VERSION 5.7 ;
  NOWIREEXTENSIONATPIN ON ;
  DIVIDERCHAR "/" ;
  BUSBITCHARS "[]" ;
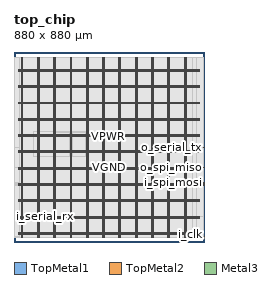
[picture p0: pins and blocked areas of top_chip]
MACRO top_chip
  CLASS BLOCK ;
  FOREIGN top_chip ;
  ORIGIN 0.000 0.000 ;
  SIZE 880.000 BY 880.000 ;
  PIN VGND
    DIRECTION INOUT ;
    USE GROUND ;
    PORT
      LAYER TopMetal1 ;
        RECT 38.860 22.050 41.060 854.910 ;
    END
    PORT
      LAYER TopMetal1 ;
        RECT 114.460 22.050 116.660 854.910 ;
    END
    PORT
      LAYER TopMetal1 ;
        RECT 190.060 22.050 192.260 854.910 ;
    END
    PORT
      LAYER TopMetal1 ;
        RECT 265.660 22.050 267.860 854.910 ;
    END
    PORT
      LAYER TopMetal1 ;
        RECT 341.260 22.050 343.460 854.910 ;
    END
    PORT
      LAYER TopMetal1 ;
        RECT 416.860 22.050 419.060 854.910 ;
    END
    PORT
      LAYER TopMetal1 ;
        RECT 492.460 22.050 494.660 854.910 ;
    END
    PORT
      LAYER TopMetal1 ;
        RECT 568.060 22.050 570.260 854.910 ;
    END
    PORT
      LAYER TopMetal1 ;
        RECT 643.660 22.050 645.860 854.910 ;
    END
    PORT
      LAYER TopMetal1 ;
        RECT 719.260 22.050 721.460 854.910 ;
    END
    PORT
      LAYER TopMetal1 ;
        RECT 794.860 22.050 797.060 854.910 ;
    END
    PORT
      LAYER TopMetal2 ;
        RECT 19.940 41.380 859.900 43.580 ;
    END
    PORT
      LAYER TopMetal2 ;
        RECT 19.940 116.980 859.900 119.180 ;
    END
    PORT
      LAYER TopMetal2 ;
        RECT 19.940 192.580 859.900 194.780 ;
    END
    PORT
      LAYER TopMetal2 ;
        RECT 19.940 268.180 859.900 270.380 ;
    END
    PORT
      LAYER TopMetal2 ;
        RECT 19.940 343.780 859.900 345.980 ;
    END
    PORT
      LAYER TopMetal2 ;
        RECT 19.940 419.380 859.900 421.580 ;
    END
    PORT
      LAYER TopMetal2 ;
        RECT 19.940 494.980 859.900 497.180 ;
    END
    PORT
      LAYER TopMetal2 ;
        RECT 19.940 570.580 859.900 572.780 ;
    END
    PORT
      LAYER TopMetal2 ;
        RECT 19.940 646.180 859.900 648.380 ;
    END
    PORT
      LAYER TopMetal2 ;
        RECT 19.940 721.780 859.900 723.980 ;
    END
    PORT
      LAYER TopMetal2 ;
        RECT 19.940 797.380 859.900 799.580 ;
    END
  END VGND
  PIN VPWR
    DIRECTION INOUT ;
    USE POWER ;
    PORT
      LAYER TopMetal1 ;
        RECT 32.660 22.460 34.860 854.500 ;
    END
    PORT
      LAYER TopMetal1 ;
        RECT 108.260 22.460 110.460 854.500 ;
    END
    PORT
      LAYER TopMetal1 ;
        RECT 183.860 22.460 186.060 854.500 ;
    END
    PORT
      LAYER TopMetal1 ;
        RECT 259.460 22.460 261.660 854.500 ;
    END
    PORT
      LAYER TopMetal1 ;
        RECT 335.060 22.460 337.260 854.500 ;
    END
    PORT
      LAYER TopMetal1 ;
        RECT 410.660 22.460 412.860 854.500 ;
    END
    PORT
      LAYER TopMetal1 ;
        RECT 486.260 22.460 488.460 854.500 ;
    END
    PORT
      LAYER TopMetal1 ;
        RECT 561.860 22.460 564.060 854.500 ;
    END
    PORT
      LAYER TopMetal1 ;
        RECT 637.460 22.460 639.660 854.500 ;
    END
    PORT
      LAYER TopMetal1 ;
        RECT 713.060 22.460 715.260 854.500 ;
    END
    PORT
      LAYER TopMetal1 ;
        RECT 788.660 22.460 790.860 854.500 ;
    END
    PORT
      LAYER TopMetal2 ;
        RECT 19.940 35.180 859.900 37.380 ;
    END
    PORT
      LAYER TopMetal2 ;
        RECT 19.940 110.780 859.900 112.980 ;
    END
    PORT
      LAYER TopMetal2 ;
        RECT 19.940 186.380 859.900 188.580 ;
    END
    PORT
      LAYER TopMetal2 ;
        RECT 19.940 261.980 859.900 264.180 ;
    END
    PORT
      LAYER TopMetal2 ;
        RECT 19.940 337.580 859.900 339.780 ;
    END
    PORT
      LAYER TopMetal2 ;
        RECT 19.940 413.180 859.900 415.380 ;
    END
    PORT
      LAYER TopMetal2 ;
        RECT 19.940 488.780 859.900 490.980 ;
    END
    PORT
      LAYER TopMetal2 ;
        RECT 19.940 564.380 859.900 566.580 ;
    END
    PORT
      LAYER TopMetal2 ;
        RECT 19.940 639.980 859.900 642.180 ;
    END
    PORT
      LAYER TopMetal2 ;
        RECT 19.940 715.580 859.900 717.780 ;
    END
    PORT
      LAYER TopMetal2 ;
        RECT 19.940 791.180 859.900 793.380 ;
    END
  END VPWR
  PIN i_clk
    DIRECTION INPUT ;
    USE SIGNAL ;
    ANTENNAGATEAREA 1.333800 ;
    ANTENNADIFFAREA 2.015400 ;
    PORT
      LAYER Metal3 ;
        RECT 879.600 27.100 880.000 27.500 ;
    END
  END i_clk
  PIN i_rst_n
    DIRECTION INPUT ;
    USE SIGNAL ;
    ANTENNAGATEAREA 0.180700 ;
    PORT
      LAYER Metal3 ;
        RECT 879.600 259.780 880.000 260.180 ;
    END
  END i_rst_n
  PIN i_serial_rx
    DIRECTION INPUT ;
    USE SIGNAL ;
    ANTENNAGATEAREA 0.180700 ;
    PORT
      LAYER Metal3 ;
        RECT 0.000 116.980 0.400 117.380 ;
    END
  END i_serial_rx
  PIN i_spi_mosi
    DIRECTION INPUT ;
    USE SIGNAL ;
    ANTENNAGATEAREA 0.180700 ;
    PORT
      LAYER Metal3 ;
        RECT 879.600 275.740 880.000 276.140 ;
    END
  END i_spi_mosi
  PIN i_spi_sclk
    DIRECTION INPUT ;
    USE SIGNAL ;
    ANTENNAGATEAREA 0.180700 ;
    PORT
      LAYER Metal3 ;
        RECT 879.600 267.340 880.000 267.740 ;
    END
  END i_spi_sclk
  PIN i_spi_ss_n
    DIRECTION INPUT ;
    USE SIGNAL ;
    ANTENNAGATEAREA 0.180700 ;
    PORT
      LAYER Metal3 ;
        RECT 879.600 269.020 880.000 269.420 ;
    END
  END i_spi_ss_n
  PIN o_serial_tx
    DIRECTION OUTPUT ;
    USE SIGNAL ;
    ANTENNADIFFAREA 0.708600 ;
    PORT
      LAYER Metal3 ;
        RECT 879.600 438.700 880.000 439.100 ;
    END
  END o_serial_tx
  PIN o_spi_miso
    DIRECTION OUTPUT ;
    USE SIGNAL ;
    ANTENNADIFFAREA 2.827200 ;
    PORT
      LAYER Metal3 ;
        RECT 879.600 345.460 880.000 345.860 ;
    END
  END o_spi_miso
  OBS
      LAYER GatPoly ;
        RECT 20.160 22.530 859.680 854.430 ;
      LAYER Metal1 ;
        RECT 20.160 22.460 859.680 854.500 ;
      LAYER Metal2 ;
        RECT 20.535 22.535 879.945 854.425 ;
      LAYER Metal3 ;
        RECT 0.400 439.310 879.985 854.380 ;
        RECT 0.400 438.490 879.390 439.310 ;
        RECT 0.400 346.070 879.985 438.490 ;
        RECT 0.400 345.250 879.390 346.070 ;
        RECT 0.400 276.350 879.985 345.250 ;
        RECT 0.400 275.530 879.390 276.350 ;
        RECT 0.400 269.630 879.985 275.530 ;
        RECT 0.400 268.810 879.390 269.630 ;
        RECT 0.400 267.950 879.985 268.810 ;
        RECT 0.400 267.130 879.390 267.950 ;
        RECT 0.400 260.390 879.985 267.130 ;
        RECT 0.400 259.570 879.390 260.390 ;
        RECT 0.400 117.590 879.985 259.570 ;
        RECT 0.610 116.770 879.985 117.590 ;
        RECT 0.400 27.710 879.985 116.770 ;
        RECT 0.400 26.890 879.390 27.710 ;
        RECT 0.400 22.580 879.985 26.890 ;
      LAYER Metal4 ;
        RECT 23.420 22.535 845.380 854.425 ;
      LAYER Metal5 ;
        RECT 32.795 22.370 828.625 854.590 ;
      LAYER TopMetal1 ;
        RECT 92.020 395.240 106.620 511.120 ;
        RECT 112.100 395.240 112.820 511.120 ;
        RECT 118.300 395.240 182.220 511.120 ;
        RECT 187.700 395.240 188.420 511.120 ;
        RECT 193.900 395.240 257.820 511.120 ;
        RECT 263.300 395.240 264.020 511.120 ;
        RECT 269.500 395.240 333.190 511.120 ;
      LAYER TopMetal2 ;
        RECT 194.440 509.000 333.240 511.000 ;
  END
END top_chip
END LIBRARY

